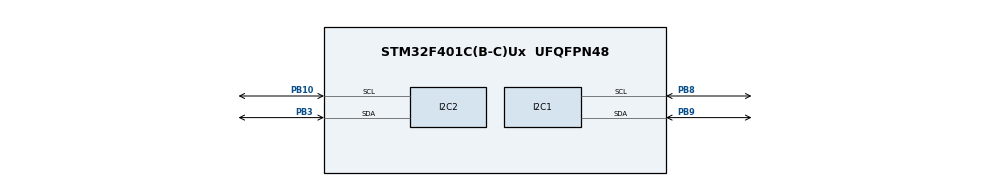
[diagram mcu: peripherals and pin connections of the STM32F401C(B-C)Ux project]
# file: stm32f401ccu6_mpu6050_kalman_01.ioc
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Mcu.Family=STM32F4
Mcu.Name=STM32F401C(B-C)Ux
Mcu.Package=UFQFPN48
NVIC.PriorityGroup=NVIC_PRIORITYGROUP_4
PA13.Mode=Serial_Wire
PA13.Signal=SYS_JTMS-SWDIO
PA14.Mode=Serial_Wire
PA14.Signal=SYS_JTCK-SWCLK
PB10.Mode=I2C
PB10.Signal=I2C2_SCL
PB3.Mode=I2C
PB3.Signal=I2C2_SDA
PB8.Mode=I2C
PB8.Signal=I2C1_SCL
PB9.Mode=I2C
PB9.Signal=I2C1_SDA
ProjectManager.HeapSize=0x200
ProjectManager.StackSize=0x400
ProjectManager.TargetToolchain=STM32CubeIDE
RCC.48MHZClocksFreq_Value=40000000
RCC.AHBFreq_Value=80000000
RCC.APB1CLKDivider=RCC_HCLK_DIV2
RCC.APB1Freq_Value=40000000
RCC.APB1TimFreq_Value=80000000
RCC.APB2Freq_Value=80000000
RCC.APB2TimFreq_Value=80000000
RCC.CortexFreq_Value=80000000
RCC.HCLKFreq_Value=80000000
RCC.HSE_VALUE=25000000
RCC.HSI_VALUE=16000000
RCC.LSE_VALUE=32768
RCC.PLLM=5
RCC.PLLN=50
RCC.SYSCLKFreq_VALUE=80000000
RCC.SYSCLKSource=RCC_SYSCLKSOURCE_PLLCLK
RCC.VCOOutputFreq_Value=160000000
board=custom

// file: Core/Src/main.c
/* USER CODE BEGIN Header */
/**
  ******************************************************************************
  * @file           : main.c
  * @brief          : Main program body
  ******************************************************************************
  * @attention
  *
  * Copyright (c) 2024 STMicroelectronics.
  * All rights reserved.
  *
  * This software is licensed under terms that can be found in the LICENSE file
  * in the root directory of this software component.
  * If no LICENSE file comes with this software, it is provided AS-IS.
  *
  ******************************************************************************
  */
/* USER CODE END Header */
#include "main.h"
/* USER CODE BEGIN Includes */
#include "lcd1602_i2c_lib.h"
#include "mpu6050_kalman.h"
#include "stdio.h"
/* USER CODE END Includes */

I2C_HandleTypeDef hi2c1;
I2C_HandleTypeDef hi2c2;

/* USER CODE BEGIN PV */
MPU6050_t MPU6050;
/* USER CODE END PV */

void SystemClock_Config(void);
static void MX_GPIO_Init(void);
static void MX_I2C1_Init(void);
static void MX_I2C2_Init(void);

int main(void)
{
  /* USER CODE BEGIN 1 */
	char buf[20];
  /* USER CODE END 1 */

  /* MCU Configuration--------------------------------------------------------*/

  /* Reset of all peripherals, Initializes the Flash interface and the Systick. */
  HAL_Init();

  /* Configure the system clock */
  SystemClock_Config();

  /* Initialize all configured peripherals */
  MX_GPIO_Init();
  MX_I2C1_Init();
  MX_I2C2_Init();
  /* USER CODE BEGIN 2 */
  HAL_Delay(100);
  lcd1602_Init();// инициализация дисплея
  lcd1602_Clean();// предварительная очистка памяти дисплея
  lcd1602_SetCursor(1, 0);// установка курсора
  while (MPU6050_Init(&hi2c1) == 1);
  /* USER CODE END 2 */

  /* Infinite loop */
  /* USER CODE BEGIN WHILE */
  while (1)
  {
	  MPU6050_Read_All(&hi2c1, &MPU6050);
	  sprintf (buf, "Angle X = %.1f", MPU6050.KalmanAngleX);// запись данных в буффер
	  lcd1602_Print_text(buf);// вывод на дисплей
	  lcd1602_SetCursor(0, 1);
	  sprintf (buf, "Angle Y = %.1f", MPU6050.KalmanAngleY);// запись данных в буффер
	  lcd1602_Print_text(buf);// вывод на дисплей
	  lcd1602_SetCursor(0, 2);
	  sprintf (buf, "Temp = %.1f", MPU6050.Temperature);// запись данных в буффер
	  lcd1602_Print_text(buf);// вывод на дисплей
	  HAL_Delay(300);
	  lcd1602_Clean();// очистка дисплея
    /* USER CODE END WHILE */

  }
}

void SystemClock_Config(void)
{
  RCC_OscInitTypeDef RCC_OscInitStruct = {0};
  RCC_ClkInitTypeDef RCC_ClkInitStruct = {0};

  /** Configure the main internal regulator output voltage
  */
  __HAL_RCC_PWR_CLK_ENABLE();
  __HAL_PWR_VOLTAGESCALING_CONFIG(PWR_REGULATOR_VOLTAGE_SCALE2);

  /** Initializes the RCC Oscillators according to the specified parameters
  * in the RCC_OscInitTypeDef structure.
  */
  RCC_OscInitStruct.OscillatorType = RCC_OSCILLATORTYPE_HSI;
  RCC_OscInitStruct.HSIState = RCC_HSI_ON;
  RCC_OscInitStruct.HSICalibrationValue = RCC_HSICALIBRATION_DEFAULT;
  RCC_OscInitStruct.PLL.PLLState = RCC_PLL_NONE;
  if (HAL_RCC_OscConfig(&RCC_OscInitStruct) != HAL_OK)
  {
    Error_Handler();
  }

  /** Initializes the CPU, AHB and APB buses clocks
  */
  RCC_ClkInitStruct.ClockType = RCC_CLOCKTYPE_HCLK|RCC_CLOCKTYPE_SYSCLK
                              |RCC_CLOCKTYPE_PCLK1|RCC_CLOCKTYPE_PCLK2;
  RCC_ClkInitStruct.SYSCLKSource = RCC_SYSCLKSOURCE_HSI;
  RCC_ClkInitStruct.AHBCLKDivider = RCC_SYSCLK_DIV1;
  RCC_ClkInitStruct.APB1CLKDivider = RCC_HCLK_DIV1;
  RCC_ClkInitStruct.APB2CLKDivider = RCC_HCLK_DIV1;

  if (HAL_RCC_ClockConfig(&RCC_ClkInitStruct, FLASH_LATENCY_0) != HAL_OK)
  {
    Error_Handler();
  }
}

static void MX_I2C1_Init(void)
{

  hi2c1.Instance = I2C1;
  hi2c1.Init.ClockSpeed = 100000;
  hi2c1.Init.DutyCycle = I2C_DUTYCYCLE_2;
  hi2c1.Init.OwnAddress1 = 0;
  hi2c1.Init.AddressingMode = I2C_ADDRESSINGMODE_7BIT;
  hi2c1.Init.DualAddressMode = I2C_DUALADDRESS_DISABLE;
  hi2c1.Init.OwnAddress2 = 0;
  hi2c1.Init.GeneralCallMode = I2C_GENERALCALL_DISABLE;
  hi2c1.Init.NoStretchMode = I2C_NOSTRETCH_DISABLE;
  if (HAL_I2C_Init(&hi2c1) != HAL_OK)
  {
    Error_Handler();
  }

}

static void MX_I2C2_Init(void)
{

  hi2c2.Instance = I2C2;
  hi2c2.Init.ClockSpeed = 100000;
  hi2c2.Init.DutyCycle = I2C_DUTYCYCLE_2;
  hi2c2.Init.OwnAddress1 = 0;
  hi2c2.Init.AddressingMode = I2C_ADDRESSINGMODE_7BIT;
  hi2c2.Init.DualAddressMode = I2C_DUALADDRESS_DISABLE;
  hi2c2.Init.OwnAddress2 = 0;
  hi2c2.Init.GeneralCallMode = I2C_GENERALCALL_DISABLE;
  hi2c2.Init.NoStretchMode = I2C_NOSTRETCH_DISABLE;
  if (HAL_I2C_Init(&hi2c2) != HAL_OK)
  {
    Error_Handler();
  }

}

static void MX_GPIO_Init(void)
{

  /* GPIO Ports Clock Enable */
  __HAL_RCC_GPIOB_CLK_ENABLE();
  __HAL_RCC_GPIOA_CLK_ENABLE();

}

void Error_Handler(void)
{
  __disable_irq();
  while (1)
  {
  }
}
